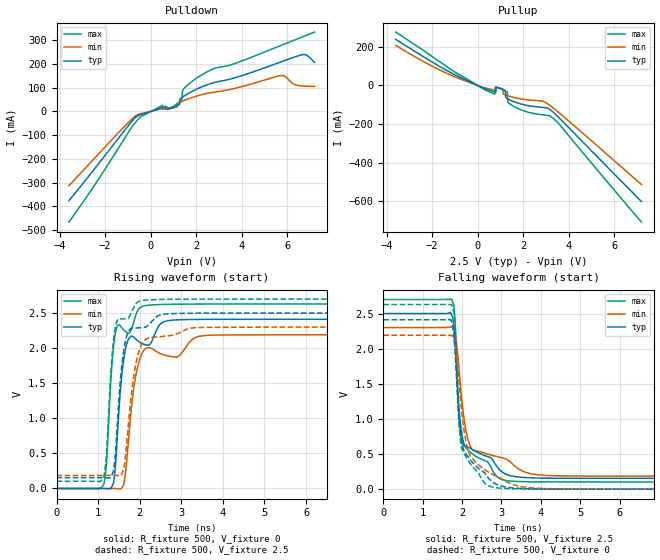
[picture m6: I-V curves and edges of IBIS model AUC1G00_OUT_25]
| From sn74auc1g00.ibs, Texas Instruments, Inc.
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[Model]   AUC1G00_OUT_25
Model_type  Output
Vref =   0
Rref =   500
Cref =   30p
Vmeas =   1.25
| variable   typ   min   max
C_comp   4.94pF   0.35pF   11.20pF
| C_pullup   5.25pF   0.35pF   11.20pF
| C_pulldown   4.63pF   0.40pF   6.58pF
[Temperature Range]   40   100   -40
| Ambient temperature   25   85   -40
[Voltage range]   2.5   2.3   2.7
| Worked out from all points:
|   slope of the pulldown table from 0 to 0.375 V, typ, clamps not added: 30.9 ohm
|   slope of the pullup table from 0 to 0.375 V, typ, clamps not added: 20 ohm
|   rising waveform, R_fixture 500, V_fixture 0: 20-80 % time 205ps typ, 264ps min, 171ps max; typ from 0 V to 2.41 V
|   falling waveform, R_fixture 500, V_fixture 2.5: 20-80 % time 235ps typ, 314ps min, 207ps max; typ from 2.5 V to 0.154 V
|   rising waveform, R_fixture 500, V_fixture 2.5: 20-80 % time 202ps typ, 262ps min, 169ps max; typ from 0.154 V to 2.5 V
|   falling waveform, R_fixture 500, V_fixture 0: 20-80 % time 300ps typ, 369ps min, 204ps max; typ from 2.41 V to 0 V
[Pulldown]
| AUC1G00_OUT_25
|   Voltage   I(typ)   I(min)   I(max)
-3.6V     -377.3mA   -313.6mA   -467.3mA
-450mV    -13.55mA   -9.199mA   -23.42mA
515mV     17.02mA    12.57mA    25.99mA
1.025V    18.9mA     15.4mA     23.61mA
1.27V     30.1mA     38.43mA    41.47mA
1.37V     59.42mA    42.49mA    49.07mA
1.395V    60.94mA    43.5mA     85.27mA
1.48V     66.06mA    46.86mA    98.94mA
2.54V     114.8mA    77.9mA     170.7mA
5.695V    208.5mA    151.4mA    277.9mA
6.74V     240.5mA    107.1mA    317.9mA
7.2V      207mA      105.8mA    335.2mA
[Pullup]
| AUC1G00_OUT_25
|   Voltage   I(typ)   I(min)   I(max)
-3.6V     239.1mA    207.3mA    276.2mA
270mV     -13.91mA   -10.31mA   -18.8mA
750mV     -32.68mA   -23.89mA   -44.27mA
770mV     -33.31mA   -24.33mA   -9.117mA
1.115V    -21.26mA   -18.82mA   -22.3mA
1.215V    -26mA      -48.89mA   -28.91mA
1.235V    -60.87mA   -49.71mA   -30.22mA
1.295V    -68.05mA   -52.07mA   -34.13mA
1.34V     -70.9mA    -53.76mA   -86.06mA
1.59V     -83.44mA   -61.97mA   -108.3mA
3.27V     -132.5mA   -111.9mA   -165.3mA
7.2V      -600.4mA   -512.6mA   -707.2mA
[Ramp]
| AUC1G00_OUT_25
| variable   typ   min   max
dV/dt_r   1.45/2.07E-10   1.32/2.66E-10   1.58/1.72E-10
dV/dt_f   1.42/2.37E-10   1.28/3.15E-10   1.56/2.07E-10
R_load = 500
[Rising Waveform]
| AUC1G00_OUT_25
R_fixture =   500
C_fixture =   0
L_fixture =   0
V_fixture =   0
V_fixture_min = 0
V_fixture_max = 0
|   Time   V(typ)   V(min)   V(max)
0s        8.552nV    24.69nV    1.796nV
1.135ns   -79.24uV   97.45uV    57.77mV
1.195ns   -2.587mV   124.1uV    331.7mV
1.38ns    124.7mV    -573.3uV   2.075V
1.585ns   1.699V     22.68mV    2.278V
1.88ns    2.146V     1.525V     2.423V
2.135ns   2.046V     1.99V      2.607V
2.98ns    2.405V     1.91V      2.627V
3.815ns   2.412V     2.187V     2.629V
24.99ns   2.412V     2.192V     2.629V
[Falling Waveform]
| AUC1G00_OUT_25
R_fixture =   500
C_fixture =   0
L_fixture =   0
V_fixture =   2.5
V_fixture_min = 2.3
V_fixture_max = 2.7
|   Time   V(typ)   V(min)   V(max)
0s        2.5V       2.3V       2.7V
1.735ns   2.483V     2.313V     2.706V
1.815ns   2.153V     2.222V     2.443V
1.915ns   1.195V     1.76V      1.079V
1.995ns   781.6mV    1.251V     653.1mV
2.105ns   609.2mV    817.4mV    585.7mV
2.25ns    567.4mV    565.9mV    506.8mV
3.11ns    213.6mV    428.3mV    123.5mV
4.39ns    155.7mV    190.8mV    103.1mV
24.99ns   154.5mV    186.3mV    102.6mV
[Rising Waveform]
| AUC1G00_OUT_25
R_fixture =   500
C_fixture =   0
L_fixture =   0
V_fixture =   2.5
V_fixture_min = 2.3
V_fixture_max = 2.7
|   Time   V(typ)   V(min)   V(max)
0s        154.5mV    186.3mV    102.6mV
1.135ns   154.4mV    186.3mV    154.9mV
1.195ns   152.6mV    186.3mV    446.2mV
1.37ns    263.7mV    186mV      2.117V
1.555ns   1.671V     194.7mV    2.417V
1.725ns   2.232V     891.1mV    2.429V
1.87ns    2.289V     1.653V     2.595V
2.06ns    2.295V     2.067V     2.679V
3.53ns    2.499V     2.296V     2.7V
24.99ns   2.5V       2.3V       2.7V
[Falling Waveform]
| AUC1G00_OUT_25
R_fixture =   500
C_fixture =   0
L_fixture =   0
V_fixture =   0
V_fixture_min = 0
V_fixture_max = 0
|   Time   V(typ)   V(min)   V(max)
0s        2.412V     2.192V     2.629V
1.735ns   2.381V     2.188V     2.629V
1.81ns    2.052V     2.086V     2.383V
1.91ns    1.1V       1.595V     1.026V
1.985ns   702.1mV    1.125V     593mV
2.085ns   514.2mV    719.2mV    474.8mV
2.205ns   419.8mV    472.2mV    364.9mV
2.805ns   90.13mV    202.1mV    26.34mV
4.48ns    634.8uV    3.242mV    95.89uV
24.99ns   17.47uV    1.171uV    8.314uV
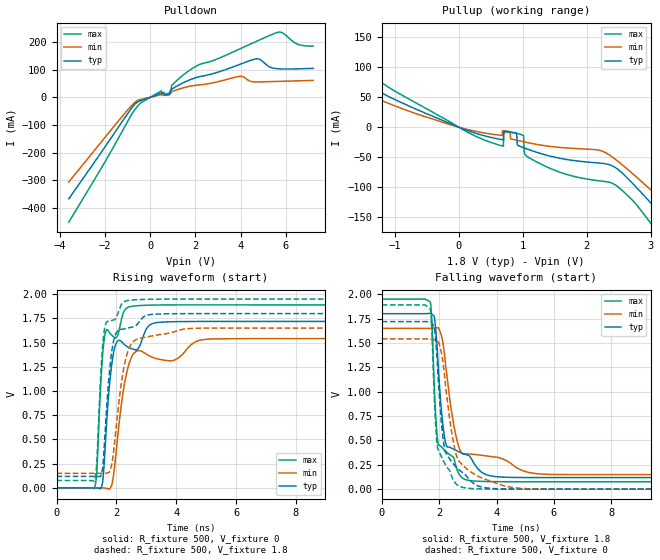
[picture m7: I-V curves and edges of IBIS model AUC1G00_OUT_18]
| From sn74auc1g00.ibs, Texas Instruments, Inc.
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[Model]   AUC1G00_OUT_18
Model_type  Output
Vref =   0
Rref =   1000
Cref =   30p
Vmeas =   0.9
| variable   typ   min   max
C_comp   5.32pF   0.60pF   8.00pF
| C_pullup   4.87pF   0.60pF   8.00pF
| C_pulldown   5.77pF   2.98pF   7.77pF
[Temperature Range]   40   100   -40
| Ambient temperature   25   85   -40
[Voltage range]   1.8   1.65   1.95
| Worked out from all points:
|   slope of the pulldown table from 0 to 0.27 V, typ, clamps not added: 34.4 ohm
|   slope of the pullup table from 0 to 0.27 V, typ, clamps not added: 25.8 ohm
|   rising waveform, R_fixture 500, V_fixture 0: 20-80 % time 283ps typ, 408ps min, 206ps max; typ from 0 V to 1.72 V
|   falling waveform, R_fixture 500, V_fixture 1.8: 20-80 % time 317ps typ, 470ps min, 216ps max; typ from 1.8 V to 0.119 V
|   rising waveform, R_fixture 500, V_fixture 1.8: 20-80 % time 274ps typ, 392ps min, 200ps max; typ from 0.119 V to 1.8 V
|   falling waveform, R_fixture 500, V_fixture 0: 20-80 % time 377ps typ, 487ps min, 249ps max; typ from 1.72 V to 0 V
[Pulldown]
| AUC1G00_OUT_18
|   Voltage   I(typ)   I(min)   I(max)
-3.6V     -367.3mA   -306.5mA   -451.8mA
-840mV    -41.05mA   -31.3mA    -64.3mA
-415mV    -11.62mA   -7.635mA   -20.14mA
495mV     14.95mA    10.62mA    23.51mA
885mV     12.29mA    19.09mA    15.87mA
925mV     28.57mA    20.19mA    16.9mA
960mV     30.15mA    21.18mA    44.34mA
2.04V     71.84mA    43.97mA    113.3mA
3.92V     118.2mA    75.81mA    173.7mA
4.62V     138.3mA    55.96mA    199.9mA
5.58V     103.9mA    57.6mA     233.8mA
7.2V      105mA      61.31mA    185.3mA
[Pullup]
| AUC1G00_OUT_18
|   Voltage   I(typ)   I(min)   I(max)
-3.6V     215mA      179.4mA    252.8mA
-2.445V   134.8mA    108.9mA    167.3mA
180mV     -7.255mA   -4.936mA   -10.74mA
695mV     -21.26mA   -6.091mA   -31.84mA
705mV     -6.765mA   -6.195mA   -7.539mA
905mV     -10.02mA   -21.84mA   -10.38mA
970mV     -32.61mA   -23.38mA   -12.15mA
1.1V      -37.67mA   -26.38mA   -51.15mA
2.235V    -60.44mA   -39.79mA   -90.27mA
3.15V     -144.2mA   -119.3mA   -181.8mA
3.985V    -243.7mA   -203mA     -300.2mA
7.2V      -625mA     -531.8mA   -746.1mA
[Ramp]
| AUC1G00_OUT_18
| variable   typ   min   max
dV/dt_r   1.04/2.84E-10   0.93/4.11E-10   1.14/2.07E-10
dV/dt_f   1.01/3.18E-10   0.91/4.80E-10   1.12/2.41E-10
R_load = 500
[Rising Waveform]
| AUC1G00_OUT_18
R_fixture =   500
C_fixture =   0
L_fixture =   0
V_fixture =   0
V_fixture_min = 0
V_fixture_max = 0
|   Time   V(typ)   V(min)   V(max)
0s        6.473nV    21.42nV    1.057nV
1.265ns   -869uV     153.9uV    -6.779mV
1.34ns    -1.674mV   211.8uV    140.5mV
1.515ns   24.13mV    -87.51uV   1.265V
1.615ns   365.9mV    -1.314mV   1.578V
1.93ns    1.431V     193.7mV    1.555V
2.46ns    1.443V     1.317V     1.872V
3.67ns    1.714V     1.315V     1.89V
5.16ns    1.719V     1.538V     1.89V
24.99ns   1.719V     1.542V     1.89V
[Falling Waveform]
| AUC1G00_OUT_18
R_fixture =   500
C_fixture =   0
L_fixture =   0
V_fixture =   1.8
V_fixture_min = 1.65
V_fixture_max = 1.95
|   Time   V(typ)   V(min)   V(max)
0s        1.8V       1.65V      1.95V
1.695ns   1.804V     1.649V     1.918V
1.83ns    1.771V     1.653V     1.041V
1.965ns   1.27V      1.658V     461.1mV
2.095ns   752.8mV    1.556V     426.9mV
2.245ns   450.1mV    1.22V      383.3mV
2.625ns   392.2mV    494.4mV    197.1mV
2.975ns   350.1mV    361.4mV    93.35mV
4.37ns    121.8mV    288.8mV    76.5mV
24.99ns   118.7mV    149.7mV    76.31mV
[Rising Waveform]
| AUC1G00_OUT_18
R_fixture =   500
C_fixture =   0
L_fixture =   0
V_fixture =   1.8
V_fixture_min = 1.65
V_fixture_max = 1.95
|   Time   V(typ)   V(min)   V(max)
0s        118.7mV    149.7mV    76.3mV
1.265ns   118.5mV    149.7mV    71.32mV
1.34ns    118.3mV    149.7mV    235.9mV
1.5ns     143.7mV    149.7mV    1.29V
1.605ns   488mV      149.1mV    1.644V
1.745ns   1.119V     158.9mV    1.72V
1.89ns    1.493V     334.2mV    1.733V
2.33ns    1.647V     1.355V     1.932V
4.56ns    1.8V       1.648V     1.95V
24.99ns   1.8V       1.65V      1.95V
[Falling Waveform]
| AUC1G00_OUT_18
R_fixture =   500
C_fixture =   0
L_fixture =   0
V_fixture =   0
V_fixture_min = 0
V_fixture_max = 0
|   Time   V(typ)   V(min)   V(max)
0s        1.719V     1.542V     1.89V
1.695ns   1.716V     1.541V     1.842V
1.745ns   1.701V     1.538V     1.625V
1.83ns    1.661V     1.532V     933.4mV
1.945ns   1.237V     1.522V     420.5mV
2.2ns     396.4mV    1.127V     261.1mV
2.52ns    249.3mV    447.6mV    80.19mV
2.795ns   173.6mV    254.1mV    20.18mV
5.115ns   215.7uV    4.021mV    -82.07uV
24.99ns   20.79uV    2.585uV    9.333uV
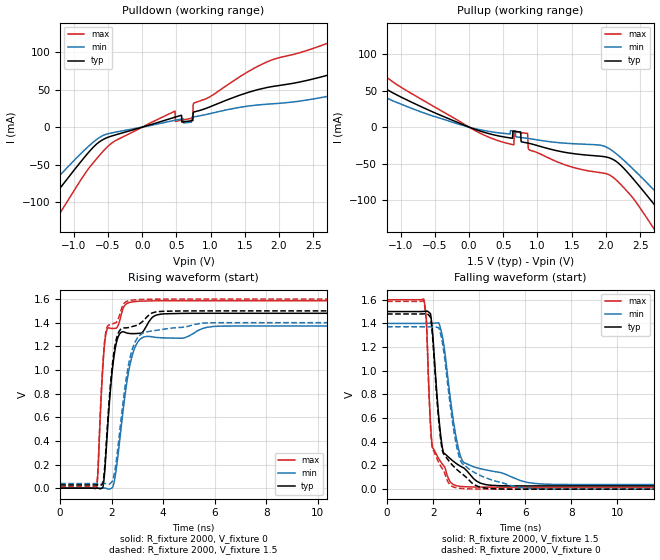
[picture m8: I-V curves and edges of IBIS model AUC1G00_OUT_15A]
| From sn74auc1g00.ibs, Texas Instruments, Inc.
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[Model]   AUC1G00_OUT_15A
Model_type  Output
Vref =   0
Rref =   2000
Cref =   15p
Vmeas =   0.75
| variable   typ   min   max
C_comp   6.59pF   0.06pF   14.96pF
| C_pullup   4.83pF   0.06pF   9.30pF
| C_pulldown   8.35pF   2.15pF   14.96pF
[Temperature Range]   40   100   -40
| Ambient temperature   25   85   -40
[Voltage range]   1.5   1.4   1.6
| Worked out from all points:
|   slope of the pulldown table from 0 to 0.225 V, typ, clamps not added: 36.6 ohm
|   slope of the pullup table from 0 to 0.225 V, typ, clamps not added: 31.2 ohm
|   rising waveform, R_fixture 2000, V_fixture 0: 20-80 % time 361ps typ, 524ps min, 249ps max; typ from 0 V to 1.48 V
|   falling waveform, R_fixture 2000, V_fixture 1.5: 20-80 % time 412ps typ, 613ps min, 298ps max; typ from 1.5 V to 0.027 V
|   rising waveform, R_fixture 2000, V_fixture 1.5: 20-80 % time 354ps typ, 516ps min, 245ps max; typ from 0.027 V to 1.5 V
|   falling waveform, R_fixture 2000, V_fixture 0: 20-80 % time 452ps typ, 623ps min, 301ps max; typ from 1.48 V to 0 V
[Pulldown]
| AUC1G00_OUT_15A
|   Voltage   I(typ)   I(min)   I(max)
-3.6V     -362.7mA   -303.6mA   -444.4mA
-2.14V    -192.5mA   -156.8mA   -246.4mA
-1.825V   -155.4mA   -125.4mA   -203.1mA
-1.36V    -100.2mA   -79.41mA   -137.7mA
-405mV    -10.71mA   -6.927mA   -18.81mA
480mV     13.33mA    9.224mA    21.44mA
485mV     13.46mA    9.315mA    7.619mA
735mV     8.725mA    13.4mA     12.06mA
755mV     20.22mA    13.7mA     32.02mA
1.69V     50.1mA     29.63mA    81.31mA
3.34V     86.08mA    49.9mA     134.3mA
7.2V      80.61mA    45.5mA     141.2mA
[Pullup]
| AUC1G00_OUT_15A
|   Voltage   I(typ)   I(min)   I(max)
-3.6V     202.5mA    153.4mA    240.8mA
-2.76V    146.2mA    116.9mA    180mA
-2.16V    107.4mA    84.79mA    136.5mA
100mV     -3.477mA   -2.309mA   -5.381mA
650mV     -5.619mA   -5.078mA   -24.2mA
660mV     -5.721mA   -5.161mA   -6.383mA
855mV     -21.78mA   -15.41mA   -8.691mA
885mV     -22.39mA   -15.82mA   -31.42mA
2.09V     -43.64mA   -32.03mA   -67.73mA
2.74V     -109.9mA   -89.68mA   -144.6mA
3.355V    -182.4mA   -150.2mA   -231.7mA
7.2V      -636.8mA   -541.5mA   -763.9mA
[Ramp]
| AUC1G00_OUT_15A
| variable   typ   min   max
dV/dt_r   0.89/3.62E-10   0.83/5.29E-10   0.95/2.50E-10
dV/dt_f   0.89/4.21E-10   0.82/6.15E-10   0.95/3.01E-10
R_load = 2000
[Rising Waveform]
| AUC1G00_OUT_15A
R_fixture =   2000
C_fixture =   0
L_fixture =   0
V_fixture =   0
V_fixture_min = 0
V_fixture_max = 0
|   Time   V(typ)   V(min)   V(max)
0s        6.138nV    22.63nV    845.8pV
1.425ns   319.6uV    182uV      9.283mV
1.66ns    6.201mV    349.4uV    1.03V
1.775ns   276.8mV    -1.361mV   1.302V
1.97ns    872.4mV    -3.277mV   1.352V
2.155ns   1.2V       123.6mV    1.352V
2.695ns   1.309V     1.027V     1.571V
3.205ns   1.321V     1.275V     1.583V
5.99ns    1.48V      1.369V     1.586V
24.99ns   1.48V      1.372V     1.586V
[Falling Waveform]
| AUC1G00_OUT_15A
R_fixture =   2000
C_fixture =   0
L_fixture =   0
V_fixture =   1.5
V_fixture_min = 1.4
V_fixture_max = 1.6
|   Time   V(typ)   V(min)   V(max)
0s        1.5V       1.4V       1.6V
1.595ns   1.502V     1.4V       1.604V
1.705ns   1.504V     1.4V       1.437V
1.855ns   1.488V     1.401V     682.5mV
1.965ns   1.351V     1.401V     363.5mV
2.405ns   347.8mV    1.286V     210.3mV
2.985ns   219.5mV    452.2mV    30.55mV
3.345ns   177.2mV    223.5mV    20.77mV
6.42ns    27.18mV    47.4mV     16.43mV
24.99ns   27.2mV     38.78mV    16.41mV
[Rising Waveform]
| AUC1G00_OUT_15A
R_fixture =   2000
C_fixture =   0
L_fixture =   0
V_fixture =   1.5
V_fixture_min = 1.4
V_fixture_max = 1.6
|   Time   V(typ)   V(min)   V(max)
0s        27.17mV    38.78mV    16.4mV
1.425ns   27.46mV    38.91mV    28.74mV
1.66ns    41.04mV    39.04mV    1.059V
1.765ns   290.8mV    38.12mV    1.311V
1.955ns   880mV      41.2mV     1.383V
2.13ns    1.207V     155.8mV    1.398V
2.635ns   1.358V     1.018V     1.584V
3.18ns    1.406V     1.307V     1.597V
5.56ns    1.5V       1.397V     1.6V
24.99ns   1.5V       1.4V       1.6V
[Falling Waveform]
| AUC1G00_OUT_15A
R_fixture =   2000
C_fixture =   0
L_fixture =   0
V_fixture =   0
V_fixture_min = 0
V_fixture_max = 0
|   Time   V(typ)   V(min)   V(max)
0s        1.48V      1.372V     1.586V
1.595ns   1.481V     1.371V     1.588V
1.705ns   1.482V     1.371V     1.415V
1.85ns    1.462V     1.371V     673.9mV
1.96ns    1.328V     1.371V     353.3mV
2.375ns   356.8mV    1.266V     180.2mV
2.935ns   183.2mV    452mV      14.98mV
3.525ns   83.62mV    175.2mV    2.645mV
5.96ns    28.51uV    9.221mV    3.068uV
24.99ns   24.8uV     3.224uV    10.37uV
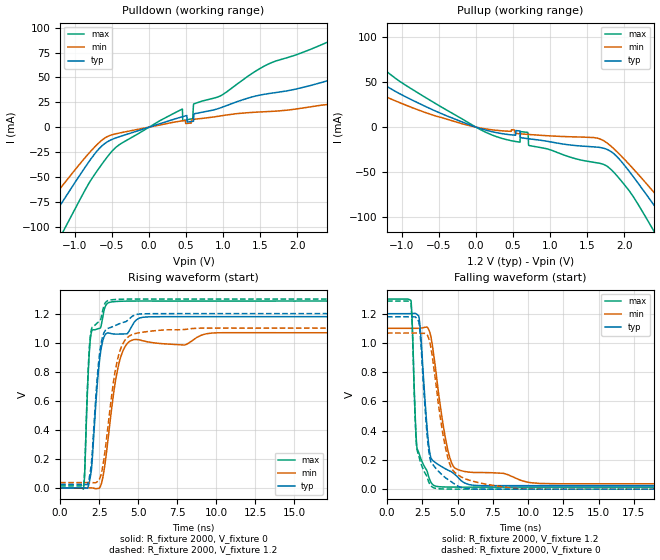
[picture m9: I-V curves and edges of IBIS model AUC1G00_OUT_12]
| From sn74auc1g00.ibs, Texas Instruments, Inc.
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[Model]   AUC1G00_OUT_12
Model_type  Output
Vref =   0
Rref =   2000
Cref =   15p
Vmeas =   0.6
| variable   typ   min   max
C_comp   8.57pF   0.79pF   20.70pF
| C_pullup   6.22pF   0.79pF   15.56pF
| C_pulldown   10.93pF   4.19pF   20.70pF
[Temperature Range]   40   100   -40
| Ambient temperature   25   85   -40
[Voltage range]   1.2   1.1   1.3
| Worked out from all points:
|   slope of the pulldown table from 0 to 0.18 V, typ, clamps not added: 41.7 ohm
|   slope of the pullup table from 0 to 0.18 V, typ, clamps not added: 41 ohm
|   rising waveform, R_fixture 2000, V_fixture 0: 20-80 % time 522ps typ, 829ps min, 318ps max; typ from 0 V to 1.18 V
|   falling waveform, R_fixture 2000, V_fixture 1.2: 20-80 % time 559ps typ, 1ns min, 330ps max; typ from 1.2 V to 0.024 V
|   rising waveform, R_fixture 2000, V_fixture 1.2: 20-80 % time 510ps typ, 815ps min, 313ps max; typ from 0.024 V to 1.2 V
|   falling waveform, R_fixture 2000, V_fixture 0: 20-80 % time 558ps typ, 1.03ns min, 344ps max; typ from 1.18 V to 0 V
[Pulldown]
| AUC1G00_OUT_12
|   Voltage   I(typ)   I(min)   I(max)
-3.6V     -358.1mA   -300.1mA   -438mA
-1.74V    -141.6mA   -114.1mA   -185.6mA
-1.425V   -104.9mA   -83.3mA    -142.2mA
-1.205V   -79.25mA   -62.17mA   -111.4mA
-680mV    -22.07mA   -15.95mA   -41.78mA
-400mV    -9.617mA   -5.913mA   -17.55mA
450mV     10.5mA     6.398mA    18.24mA
590mV     5.848mA    7.731mA    8.546mA
605mV     12.96mA    7.861mA    23.36mA
2.86V     55.95mA    19.1mA     100.7mA
3.425V    44.58mA    20.08mA    119.3mA
7.2V      57.06mA    26.83mA    108mA
[Pullup]
| AUC1G00_OUT_12
|   Voltage   I(typ)   I(min)   I(max)
-3.6V     173.9mA    42.58mA    229.5mA
-2.43V    113.6mA    55.21mA    146.6mA
-1.995V   87.92mA    64.35mA    115.9mA
135mV     -3.412mA   -2.017mA   -5.817mA
595mV     -4.256mA   -7.381mA   -16.72mA
700mV     -12.81mA   -8.068mA   -5.896mA
720mV     -13.01mA   -8.191mA   -20.48mA
1.785V    -25.34mA   -18.58mA   -44.31mA
2.435V    -90.31mA   -75.4mA    -120.1mA
2.73V     -124.7mA   -103.9mA   -161.8mA
3.085V    -166.4mA   -139mA     -211.7mA
7.2V      -650.2mA   -555.8mA   -779.2mA
[Ramp]
| AUC1G00_OUT_12
| variable   typ   min   max
dV/dt_r   0.71/5.30E-10   0.64/8.34E-10   0.78/3.20E-10
dV/dt_f   0.71/5.79E-10   0.64/1.03E-09   0.77/3.67E-10
R_load = 2000
[Rising Waveform]
| AUC1G00_OUT_12
R_fixture =   2000
C_fixture =   0
L_fixture =   0
V_fixture =   0
V_fixture_min = 0
V_fixture_max = 0
|   Time   V(typ)   V(min)   V(max)
0s        5.734nV    24nV       679.6pV
1.495ns   215.6uV    35.96uV    -6.8mV
1.575ns   -372uV     92.78uV    108.1mV
1.805ns   13.11mV    359uV      806.9mV
1.955ns   90.94mV    602.4uV    1.043V
2.545ns   898.1mV    4.504mV    1.099V
3.085ns   1.067V     351.6mV    1.274V
3.785ns   1.059V     865.7mV    1.284V
4.65ns    1.124V     1.019V     1.286V
24.99ns   1.179V     1.068V     1.286V
[Falling Waveform]
| AUC1G00_OUT_12
R_fixture =   2000
C_fixture =   0
L_fixture =   0
V_fixture =   1.2
V_fixture_min = 1.1
V_fixture_max = 1.3
|   Time   V(typ)   V(min)   V(max)
0s        1.2V       1.1V       1.3V
1.705ns   1.201V     1.1V       1.288V
2.055ns   1.2V       1.1V       372.9mV
2.25ns    1.185V     1.101V     249.5mV
2.92ns    334.7mV    1.098V     96.55mV
3.325ns   189.6mV    908.2mV    25.43mV
4.25ns    133.6mV    293.3mV    14.62mV
5.005ns   83.39mV    133.8mV    13.95mV
10.88ns   24.09mV    38.75mV    13.89mV
24.99ns   24.01mV    36.66mV    13.87mV
[Rising Waveform]
| AUC1G00_OUT_12
R_fixture =   2000
C_fixture =   0
L_fixture =   0
V_fixture =   1.2
V_fixture_min = 1.1
V_fixture_max = 1.3
|   Time   V(typ)   V(min)   V(max)
0s        23.98mV    36.64mV    13.86mV
1.49ns    24.13mV    36.67mV    7.183mV
1.575ns   23.81mV    36.69mV    132.9mV
1.8ns     38.65mV    36.8mV     825.7mV
1.945ns   122.1mV    36.89mV    1.056V
2.525ns   924.1mV    62.28mV    1.148V
3.06ns    1.098V     420.6mV    1.289V
3.765ns   1.129V     921.2mV    1.298V
4.775ns   1.19V      1.062V     1.3V
24.99ns   1.2V       1.1V       1.3V
[Falling Waveform]
| AUC1G00_OUT_12
R_fixture =   2000
C_fixture =   0
L_fixture =   0
V_fixture =   0
V_fixture_min = 0
V_fixture_max = 0
|   Time   V(typ)   V(min)   V(max)
0s        1.179V     1.068V     1.286V
1.705ns   1.179V     1.068V     1.27V
2.05ns    1.174V     1.068V     358.8mV
2.25ns    1.146V     1.067V     226.5mV
2.88ns    330.9mV    1.049V     71.74mV
3.255ns   167.4mV    875.1mV    12.02mV
3.855ns   102.3mV    440.7mV    1.611mV
4.31ns    66.75mV    214.7mV    543.5uV
5.475ns   6.08mV     73.61mV    1.708uV
24.99ns   29.85uV    6.719uV    11.48uV
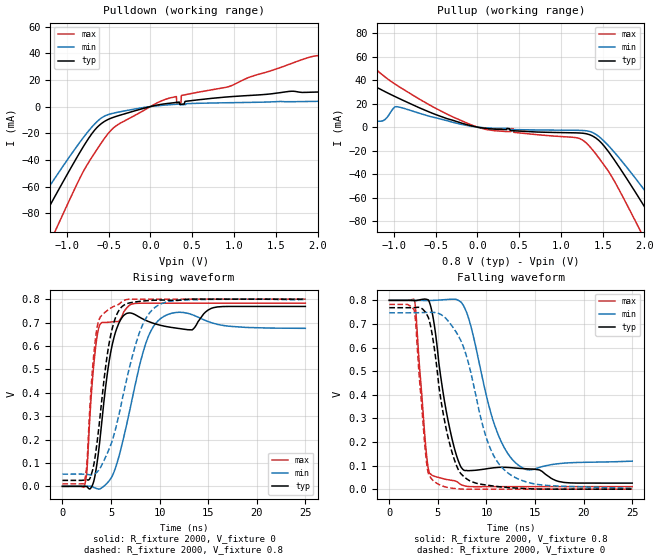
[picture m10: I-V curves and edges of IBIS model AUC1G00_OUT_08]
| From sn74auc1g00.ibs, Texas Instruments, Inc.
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[Model]   AUC1G00_OUT_08
Model_type  Output
Vref =   0
Rref =   2000
Cref =   15p
Vmeas =   0.4
| variable   typ   min   max
C_comp   11.50pF   4.34pF   28.13pF
| C_pullup   9.91pF   4.34pF   19.69pF
| C_pulldown   13.08pF   5.60pF   28.13pF
[Temperature Range]   40   100   -40
| Ambient temperature   25   85   -40
[Voltage range]   0.8   0.8   0.8
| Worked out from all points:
|   slope of the pulldown table from 0 to 0.12 V, typ, clamps not added: 77.1 ohm
|   slope of the pullup table from 0 to 0.12 V, typ, clamps not added: 98.7 ohm
|   rising waveform, R_fixture 2000, V_fixture 0: 20-80 % time 1.45ns typ, 2.22ns min, 869ps max; typ from 0 V to 0.769 V
|   falling waveform, R_fixture 2000, V_fixture 0.8: 20-80 % time 1.85ns typ, 2.43ns min, 869ps max; typ from 0.8 V to 0.026 V
|   rising waveform, R_fixture 2000, V_fixture 0.8: 20-80 % time 1.42ns typ, 2.69ns min, 817ps max; typ from 0.025 V to 0.8 V
|   falling waveform, R_fixture 2000, V_fixture 0: 20-80 % time 1.9ns typ, 2.95ns min, 884ps max; typ from 0.769 V to 0 V
[Pulldown]
| AUC1G00_OUT_08
|   Voltage   I(typ)   I(min)   I(max)
-3.6V     -351.9mA   -296.5mA   -427.3mA
-1.64V    -124.3mA   -101.1mA   -161.8mA
-1.505V   -108.7mA   -87.99mA   -143.3mA
-1.38V    -94.32mA   -75.96mA   -126.2mA
-1.16V    -69.17mA   -55.13mA   -96mA
-645mV    -16.01mA   -11.6mA    -32.55mA
-435mV    -7.893mA   -4.858mA   -15.6mA
-95mV     -1.581mA   -843.7uA   -3.47mA
210mV     2.329mA    1.254mA    6.027mA
1.98V     10.84mA    3.867mA    38.03mA
2.365V    11.74mA    4.199mA    33.49mA
7.2V      23.85mA    8.894mA    59.34mA
[Pullup]
| AUC1G00_OUT_08
|   Voltage   I(typ)   I(min)   I(max)
-3.6V     28.98mA    5.562mA    123.1mA
-1.78V    21.33mA    5.68mA     84.42mA
-1.295V   36.3mA     5.803mA    54.11mA
-1.125V   30.86mA    5.599mA    43.75mA
-970mV    25.44mA    17.41mA    35.85mA
-290mV    5.734mA    4.039mA    8.576mA
1.31V     -5.707mA   -3.159mA   -13.83mA
1.515V    -15.81mA   -11.74mA   -31.99mA
1.89V     -54.97mA   -43.18mA   -79.48mA
2.125V    -81.64mA   -65.04mA   -112.1mA
2.4V      -113.4mA   -91.38mA   -150.3mA
7.2V      -672.8mA   -574mA     -806.3mA
[Ramp]
| AUC1G00_OUT_08
| variable   typ   min   max
dV/dt_r   0.47/1.48E-09   0.45/2.57E-09   0.47/8.73E-10
dV/dt_f   0.47/1.90E-09   0.43/2.70E-09   0.48/8.82E-10
R_load = 2000
[Rising Waveform]
| AUC1G00_OUT_08
R_fixture =   2000
C_fixture =   0
L_fixture =   0
V_fixture =   0
V_fixture_min = 0
V_fixture_max = 0
|   Time   V(typ)   V(min)   V(max)
0s        7.013nV    39.16nV    506.9pV
2.315ns   -388uV     540.8uV    10.01mV
2.525ns   -1.36mV    874uV      68.83mV
3.265ns   28.27mV    -5.465mV   536.1mV
4.01ns    258.3mV    -7.428mV   698.7mV
4.94ns    566.7mV    31.31mV    702.1mV
5.995ns   712.6mV    156.1mV    716.7mV
8.45ns    711.7mV    594.6mV    782.6mV
10.09ns   688.2mV    716.6mV    782.6mV
24.99ns   768.8mV    675.2mV    782.7mV
[Falling Waveform]
| AUC1G00_OUT_08
R_fixture =   2000
C_fixture =   0
L_fixture =   0
V_fixture =   0.8
V_fixture_min = 0.8
V_fixture_max = 0.8
|   Time   V(typ)   V(min)   V(max)
0s        800mV      800mV      800mV
2.595ns   799mV      799.8mV    799.3mV
3.74ns    805mV      799.4mV    185mV
4.185ns   785.1mV    799.5mV    64.99mV
6.02ns    295.6mV    803.8mV    40.07mV
7.58ns    83.18mV    781.3mV    15.9mV
8.395ns   78.92mV    690.4mV    10.73mV
10.78ns   90.72mV    278.8mV    10.65mV
13ns      89.39mV    111.1mV    10.64mV
24.99ns   25.59mV    118.6mV    10.61mV
[Rising Waveform]
| AUC1G00_OUT_08
R_fixture =   2000
C_fixture =   0
L_fixture =   0
V_fixture =   0.8
V_fixture_min = 0.8
V_fixture_max = 0.8
|   Time   V(typ)   V(min)   V(max)
0s        25.46mV    52.25mV    10.6mV
2.245ns   26.61mV    51.79mV    16.05mV
2.5ns     28.12mV    51.06mV    85.98mV
2.98ns    51.85mV    48.84mV    438.7mV
3.465ns   156.7mV    57.61mV    652.4mV
4.64ns    569.4mV    143.8mV    752.2mV
6.035ns   764.1mV    348.1mV    786mV
7.905ns   790.1mV    654.8mV    799.8mV
9.52ns    795.3mV    764.6mV    799.8mV
24.99ns   799.9mV    798.3mV    800mV
[Falling Waveform]
| AUC1G00_OUT_08
R_fixture =   2000
C_fixture =   0
L_fixture =   0
V_fixture =   0
V_fixture_min = 0
V_fixture_max = 0
|   Time   V(typ)   V(min)   V(max)
0s        768.8mV    747.1mV    782.7mV
2.575ns   769.2mV    747.2mV    755mV
3.83ns    742mV      749mV      114.1mV
4.63ns    597.4mV    748.5mV    32.04mV
5.31ns    378.4mV    739.9mV    16.05mV
6.11ns    209mV      709.6mV    6.387mV
7.985ns   42.97mV    557.8mV    19.59uV
10.08ns   16.86mV    205.8mV    58.28uV
12.1ns    7.24mV     72.06mV    48.62uV
24.99ns   70.35uV    3.776mV    17.13uV
